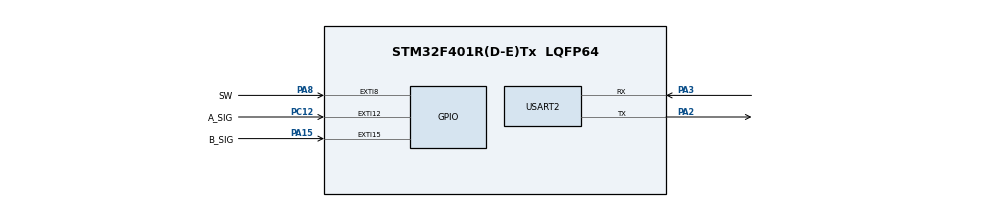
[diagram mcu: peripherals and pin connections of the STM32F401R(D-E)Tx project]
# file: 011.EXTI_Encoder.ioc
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Mcu.Family=STM32F4
Mcu.Name=STM32F401R(D-E)Tx
Mcu.Package=LQFP64
NVIC.EXTI15_10_IRQn=true\:0\:0\:false\:false\:true\:true\:true\:true
NVIC.EXTI9_5_IRQn=true\:0\:0\:false\:false\:true\:true\:true\:true
NVIC.PriorityGroup=NVIC_PRIORITYGROUP_4
PA13.Mode=Serial_Wire
PA13.Signal=SYS_JTMS-SWDIO
PA14.Mode=Serial_Wire
PA14.Signal=SYS_JTCK-SWCLK
PA15.GPIO_Label=B_SIG
PA15.GPIO_ModeDefaultEXTI=GPIO_MODE_IT_RISING
PA15.Signal=GPXTI15
PA2.Mode=Asynchronous
PA2.Signal=USART2_TX
PA3.Mode=Asynchronous
PA3.Signal=USART2_RX
PA8.GPIO_Label=SW
PA8.GPIO_ModeDefaultEXTI=GPIO_MODE_IT_FALLING
PA8.Signal=GPXTI8
PC12.GPIO_Label=A_SIG
PC12.GPIO_ModeDefaultEXTI=GPIO_MODE_IT_RISING
PC12.Signal=GPXTI12
ProjectManager.HeapSize=0x200
ProjectManager.StackSize=0x400
ProjectManager.TargetToolchain=STM32CubeIDE
RCC.48MHZClocksFreq_Value=32000000
RCC.AHBFreq_Value=64000000
RCC.APB1CLKDivider=RCC_HCLK_DIV2
RCC.APB1Freq_Value=32000000
RCC.APB1TimFreq_Value=64000000
RCC.APB2Freq_Value=64000000
RCC.APB2TimFreq_Value=64000000
RCC.CortexFreq_Value=64000000
RCC.HCLKFreq_Value=64000000
RCC.HSE_VALUE=25000000
RCC.HSI_VALUE=16000000
RCC.LSE_VALUE=32768
RCC.PLLM=8
RCC.PLLN=64
RCC.SYSCLKFreq_VALUE=64000000
RCC.SYSCLKSource=RCC_SYSCLKSOURCE_PLLCLK
RCC.VCOOutputFreq_Value=128000000
USART2.VirtualMode=VM_ASYNC
board=custom

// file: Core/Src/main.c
/* USER CODE BEGIN Header */
/**
  ******************************************************************************
  * @file           : main.c
  * @brief          : Main program body
  ******************************************************************************
  * @attention
  *
  * Copyright (c) 2025 STMicroelectronics.
  * All rights reserved.
  *
  * This software is licensed under terms that can be found in the LICENSE file
  * in the root directory of this software component.
  * If no LICENSE file comes with this software, it is provided AS-IS.
  *
  ******************************************************************************
  */
/* USER CODE END Header */
#include "main.h"

/* USER CODE BEGIN Includes */
#include <stdio.h>
/* USER CODE END Includes */

UART_HandleTypeDef huart2;

/* USER CODE BEGIN PV */
volatile int gEnCoderCnt;
/* USER CODE END PV */

void SystemClock_Config(void);
static void MX_GPIO_Init(void);
static void MX_USART2_UART_Init(void);
/* USER CODE BEGIN PFP */
#ifdef __GNUC__
#define PUTCHAR_PROTOTYPE int __io_putchar(int ch)
#else
#define PUTCHAR_PROTOTYPE int fputc(int ch, FILE *f)
#endif

PUTCHAR_PROTOTYPE
{
	if(ch == '\n')
	{
		HAL_UART_Transmit(&huart2, (uint8_t*)"\r", 1, 0xFFFF);
	}
	HAL_UART_Transmit(&huart2, (uint8_t*)&ch, 1, 0xFFFF);
	return ch;
}
/* USER CODE END PFP */

int main(void)
{

  /* MCU Configuration--------------------------------------------------------*/

  /* Reset of all peripherals, Initializes the Flash interface and the Systick. */
  HAL_Init();

  /* Configure the system clock */
  SystemClock_Config();

  /* Initialize all configured peripherals */
  MX_GPIO_Init();
  MX_USART2_UART_Init();
  /* USER CODE BEGIN 2 */

  int preEncoderCnt = 0;
  uint8_t Complete_Sig = 0;
  /* USER CODE END 2 */

  /* Infinite loop */
  while (1)
  {

	  if((preEncoderCnt != gEnCoderCnt))
	  {
		  preEncoderCnt=gEnCoderCnt;
		  printf("%d\n",preEncoderCnt);

	  }
  }
}

void SystemClock_Config(void)
{
  RCC_OscInitTypeDef RCC_OscInitStruct = {0};
  RCC_ClkInitTypeDef RCC_ClkInitStruct = {0};

  /** Configure the main internal regulator output voltage
  */
  __HAL_RCC_PWR_CLK_ENABLE();
  __HAL_PWR_VOLTAGESCALING_CONFIG(PWR_REGULATOR_VOLTAGE_SCALE2);

  /** Initializes the RCC Oscillators according to the specified parameters
  * in the RCC_OscInitTypeDef structure.
  */
  RCC_OscInitStruct.OscillatorType = RCC_OSCILLATORTYPE_HSI;
  RCC_OscInitStruct.HSIState = RCC_HSI_ON;
  RCC_OscInitStruct.HSICalibrationValue = RCC_HSICALIBRATION_DEFAULT;
  RCC_OscInitStruct.PLL.PLLState = RCC_PLL_NONE;
  if (HAL_RCC_OscConfig(&RCC_OscInitStruct) != HAL_OK)
  {
    Error_Handler();
  }

  /** Initializes the CPU, AHB and APB buses clocks
  */
  RCC_ClkInitStruct.ClockType = RCC_CLOCKTYPE_HCLK|RCC_CLOCKTYPE_SYSCLK
                              |RCC_CLOCKTYPE_PCLK1|RCC_CLOCKTYPE_PCLK2;
  RCC_ClkInitStruct.SYSCLKSource = RCC_SYSCLKSOURCE_HSI;
  RCC_ClkInitStruct.AHBCLKDivider = RCC_SYSCLK_DIV1;
  RCC_ClkInitStruct.APB1CLKDivider = RCC_HCLK_DIV1;
  RCC_ClkInitStruct.APB2CLKDivider = RCC_HCLK_DIV1;

  if (HAL_RCC_ClockConfig(&RCC_ClkInitStruct, FLASH_LATENCY_0) != HAL_OK)
  {
    Error_Handler();
  }
}

static void MX_USART2_UART_Init(void)
{

  huart2.Instance = USART2;
  huart2.Init.BaudRate = 115200;
  huart2.Init.WordLength = UART_WORDLENGTH_8B;
  huart2.Init.StopBits = UART_STOPBITS_1;
  huart2.Init.Parity = UART_PARITY_NONE;
  huart2.Init.Mode = UART_MODE_TX_RX;
  huart2.Init.HwFlowCtl = UART_HWCONTROL_NONE;
  huart2.Init.OverSampling = UART_OVERSAMPLING_16;
  if (HAL_UART_Init(&huart2) != HAL_OK)
  {
    Error_Handler();
  }

}

static void MX_GPIO_Init(void)
{
  GPIO_InitTypeDef GPIO_InitStruct = {0};

  /* GPIO Ports Clock Enable */
  __HAL_RCC_GPIOA_CLK_ENABLE();
  __HAL_RCC_GPIOC_CLK_ENABLE();

  /*Configure GPIO pin : SW_Pin */
  GPIO_InitStruct.Pin = SW_Pin;
  GPIO_InitStruct.Mode = GPIO_MODE_IT_FALLING;
  GPIO_InitStruct.Pull = GPIO_NOPULL;
  HAL_GPIO_Init(SW_GPIO_Port, &GPIO_InitStruct);

  /*Configure GPIO pin : B_SIG_Pin */
  GPIO_InitStruct.Pin = B_SIG_Pin;
  GPIO_InitStruct.Mode = GPIO_MODE_IT_RISING;
  GPIO_InitStruct.Pull = GPIO_NOPULL;
  HAL_GPIO_Init(B_SIG_GPIO_Port, &GPIO_InitStruct);

  /*Configure GPIO pin : A_SIG_Pin */
  GPIO_InitStruct.Pin = A_SIG_Pin;
  GPIO_InitStruct.Mode = GPIO_MODE_IT_RISING;
  GPIO_InitStruct.Pull = GPIO_NOPULL;
  HAL_GPIO_Init(A_SIG_GPIO_Port, &GPIO_InitStruct);

  /* EXTI interrupt init*/
  HAL_NVIC_SetPriority(EXTI9_5_IRQn, 0, 0);
  HAL_NVIC_EnableIRQ(EXTI9_5_IRQn);

  HAL_NVIC_SetPriority(EXTI15_10_IRQn, 0, 0);
  HAL_NVIC_EnableIRQ(EXTI15_10_IRQn);

}

/* USER CODE BEGIN 4 */
void HAL_GPIO_EXTI_Callback(uint16_t GPIO_Pin)
{
	switch(GPIO_Pin)
	{
	case GPIO_PIN_8 :
		gEnCoderCnt = 0;
		break;

	case GPIO_PIN_12 :
		if(!HAL_GPIO_ReadPin(B_SIG_GPIO_Port, B_SIG_Pin))
		{
			gEnCoderCnt++;
		}
		break;

	case GPIO_PIN_15 :
		if(!HAL_GPIO_ReadPin(A_SIG_GPIO_Port, A_SIG_Pin))
		{
			gEnCoderCnt--;
		}
		break;

	default :
		break;
	}
}
/* USER CODE END 4 */

void Error_Handler(void)
{
  __disable_irq();
  while (1)
  {
  }
}
